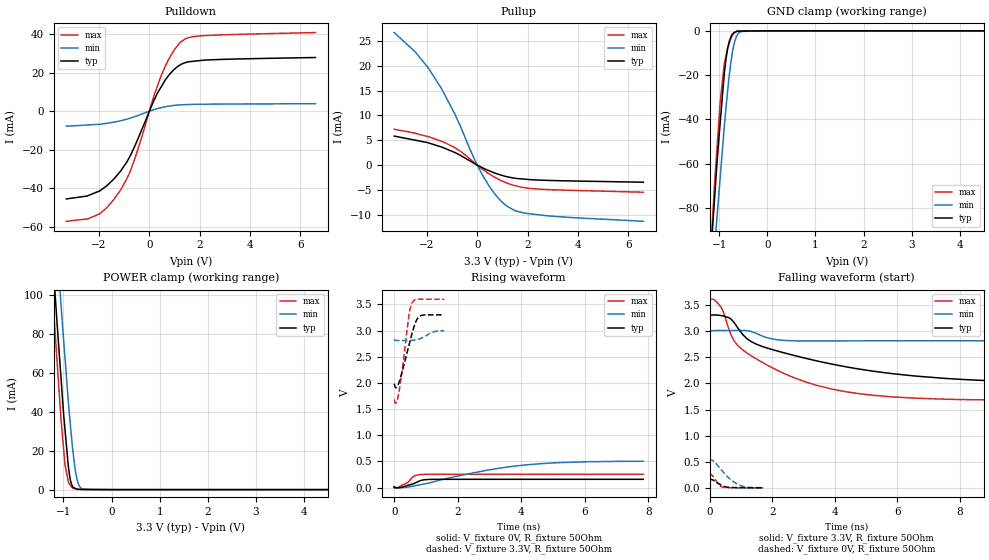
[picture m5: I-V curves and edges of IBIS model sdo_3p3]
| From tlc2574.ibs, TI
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|   sdo_3p3 Model
[Model]   sdo_3p3
Model_type   3-state
Polarity   Non-Inverting
Vmeas = 1.65
Vref = 1.65
Cref = 2pF
Rref = 50
|   typ   min   max
C_comp   1.252e-12   1.247e-12   1.334e-12
[Voltage Range]   3.3   3   3.6
|Ambient Temperature   25   85   -40
|Junction Temperature
[Temperature Range]   27   125   -40
[Pullup Reference]   3.3   3   3.6
[Pulldown Reference]   0   0   0
[Power Clamp Reference]   3.3   3   3.6
[GND Clamp Reference]   0   0   0
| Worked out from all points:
|   slope of the pulldown table from 0 to 0.495 V, typ, clamps not added: 37.5 ohm
|   slope of the pullup table from 0 to 0.495 V, typ, clamps not added: 415 ohm
|   GND clamp passes 1 mA (typ) near -0.70 V on its own axis
|   POWER clamp passes 1 mA (typ) near -0.79 V on its own axis
|   falling waveform, V_fixture 3.3V, R_fixture 50Ohm: 20-80 % time 4.08ns typ, 538ps min, 2.41ns max; typ from 3.3 V to 1.99 V
|   rising waveform, V_fixture 0V, R_fixture 50Ohm: 20-80 % time 423ps typ, 2.51ns min, 324ps max; typ from 0 V to 0.157 V
|   rising waveform, V_fixture 3.3V, R_fixture 50Ohm: 20-80 % time 342ps typ, 337ps min, 239ps max; typ from 1.98 V to 3.3 V
|   falling waveform, V_fixture 0V, R_fixture 50Ohm: 20-80 % time 268ps typ, 508ps min, 172ps max; typ from 0.157 V to 0.001 V
[Pulldown]
|   Voltage   I(typ)   I(min)   I(max)
-3.3V     -45.52mA   -7.788mA   -57.14mA
-2.444V   -43.84mA   -7.138mA   -55.88mA
-1.969V   -41.36mA   -6.778mA   -53.25mA
-1.134V   -30.95mA   -4.947mA   -40.69mA
-734.4mV  -22.56mA   -3.482mA   -30.43mA
174.9mV   5.391mA    753.1uA    7.611mA
478.8mV   12.83mA    1.859mA    18.69mA
810mV     19.22mA    2.712mA    27.92mA
1.246V    24.24mA    3.317mA    35.95mA
1.454V    25.32mA    3.414mA    37.77mA
2.167V    26.5mA     3.633mA    39.22mA
6.6V      27.87mA    3.884mA    40.82mA
[GND Clamp]
|   Voltage   I(typ)   I(min)   I(max)
-3.3V     -922.7mA   -873.5mA   -986.9mA
-1.211V   -112mA     -132.8mA   -110.7mA
-1.102V   -76.91mA   -99.77mA   -70.34mA
-1.056V   -62.3mA    -86.52mA   -55.75mA
-982.8mV  -42.01mA   -66.74mA   -32.51mA
-896.4mV  -19.48mA   -43.41mA   -14.99mA
-861.3mV  -12.87mA   -35.02mA   -11.28mA
-756mV    -2.692mA   -13.81mA   -3.279mA
-648mV    -381.4uA   -2.804mA   -327uA
-552mV    -127.7uA   -329.8uA   -62.08uA
-285mV    -65.55uA   -302.6nA   -104.3nA
6.6V      0A         0A         0A
[Pullup]
|   Voltage   I(typ)   I(min)   I(max)
-3.3V     5.835mA    26.67mA    7.196mA
-2.46V    5.002mA    22.76mA    6.382mA
-1.932V   4.453mA    19.45mA    5.697mA
-1.419V   3.64mA     15.36mA    4.786mA
-897mV    2.549mA    10.32mA    3.531mA
-159mV    451.6uA    1.703mA    671.7uA
228mV     -593.2uA   -2.193mA   -897.2uA
690mV     -1.592mA   -5.779mA   -2.433mA
1.155V    -2.313mA   -8.194mA   -3.58mA
1.86V     -2.826mA   -9.646mA   -4.543mA
2.781V    -3.081mA   -10.21mA   -4.93mA
6.6V      -3.456mA   -11.32mA   -5.468mA
[POWER Clamp]
|   Voltage   I(typ)   I(min)   I(max)
-3.3V     968.7mA    980.7mA    975.5mA
-1.356V   169.5mA    206.7mA    152.6mA
-1.195V   108.6mA    146.8mA    88.93mA
-1.185V   104.8mA    143.1mA    85.09mA
-1.139V   87.74mA    126.6mA    68.23mA
-1.051V   57.71mA    95.77mA    36.57mA
-968.4mV  31.07mA    68.06mA    12.9mA
-897.6mV  11.81mA    45.18mA    3.912mA
-806.4mV  1.497mA    20.64mA    866.2uA
-714mV    214.9uA    4.938mA    373.3uA
-591mV    104.7uA    223.6uA    35.79uA
6.6V      0A         0A         0A
[Ramp]
R_load = 50
|   typ   min   max
dV/dt_r   0.0940914/4.23437e-10   0.302009/2.5121e-09   0.151352/3.22964e-10
dV/dt_f   0.79027/4.15044e-09   0.111339/5.273e-10   1.15667/2.40425e-09
[Falling Waveform]
V_fixture = 3.3V
V_fixture_min = 3V
V_fixture_max = 3.6V
R_fixture = 50Ohm
|   Time   V(typ)   V(min)   V(max)
0s        3.3V       3V         3.6V
145ps     3.309V     3.011V     3.601V
365ps     3.299V     3.012V     3.458V
755ps     3.183V     3.013V     2.844V
1.055ns   2.937V     3.013V     2.64V
1.725ns   2.697V     2.896V     2.388V
2.735ns   2.529V     2.814V     2.1V
3.95ns    2.363V     2.813V     1.886V
8.03ns    2.077V     2.814V     1.691V
14.85ns   1.991V     2.814V     1.673V
[Rising Waveform]
V_fixture = 0V
V_fixture_min = 0V
V_fixture_max = 0V
R_fixture = 50Ohm
|   Time   V(typ)   V(min)   V(max)
0s        1.558nV    3.443nV    1.357nV
5ps       17.43mV    6.245mV    16.31mV
105ps     -6.062mV   -4.033mV   -2.137mV
410ps     37.81mV    6.946mV    89.24mV
630ps     77.34mV    30.53mV    217.5mV
895ps     142.5mV    60.85mV    250.1mV
2.795ns   156.8mV    316.3mV    252.2mV
4.115ns   156.8mV    430.2mV    252.2mV
5.285ns   156.8mV    477.8mV    252.2mV
7.845ns   156.8mV    502.3mV    252.2mV
[Rising Waveform]
V_fixture = 3.3V
V_fixture_min = 3V
V_fixture_max = 3.6V
R_fixture = 50Ohm
|   Time   V(typ)   V(min)   V(max)
0s        1.983V     2.814V     1.672V
65ps      1.909V     2.81V      1.621V
145ps     1.997V     2.809V     1.808V
265ps     2.249V     2.81V      2.309V
470ps     2.73V      2.811V     3.311V
560ps     2.939V     2.813V     3.523V
700ps     3.193V     2.824V     3.595V
835ps     3.283V     2.848V     3.601V
1.23ns    3.3V       2.973V     3.599V
1.575ns   3.3V       2.998V     3.599V
[Falling Waveform]
V_fixture = 0V
V_fixture_min = 0V
V_fixture_max = 0V
R_fixture = 50Ohm
|   Time   V(typ)   V(min)   V(max)
0s        156.8mV    503.3mV    252.3mV
50ps      160.6mV    530.1mV    255.3mV
120ps     145.7mV    514mV      214.9mV
270ps     88.57mV    418.8mV    75.05mV
400ps     43.33mV    325.7mV    18.79mV
545ps     14.99mV    230.5mV    6.913mV
680ps     7.406mV    155.7mV    3.521mV
965ps     4.201mV    50.33mV    1.11mV
1.225ns   2.023mV    11.73mV    757.3uV
1.715ns   712.6uV    3.15mV     658.5uV
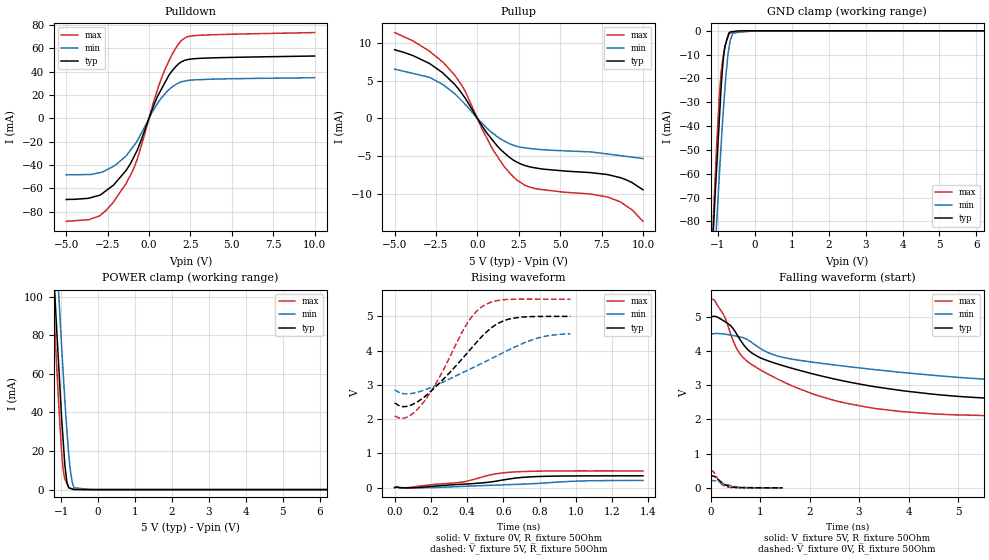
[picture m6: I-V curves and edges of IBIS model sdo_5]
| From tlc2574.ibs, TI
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|   sdo_5 Model
[Model]   sdo_5
Model_type   3-state
Polarity   Non-Inverting
Vmeas = 2.5
Vref = 2.5
Cref = 2pF
Rref = 50
|   typ   min   max
C_comp   1.148e-12   1.143e-12   1.168e-12
[Voltage Range]   5   4.5   5.5
|Ambient Temperature   25   85   -40
|Junction Temperature
[Temperature Range]   27   125   -40
[Pullup Reference]   5   4.5   5.5
[Pulldown Reference]   0   0   0
[Power Clamp Reference]   5   4.5   5.5
[GND Clamp Reference]   0   0   0
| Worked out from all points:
|   slope of the pulldown table from 0 to 0.75 V, typ, clamps not added: 30 ohm
|   slope of the pullup table from 0 to 0.75 V, typ, clamps not added: 310 ohm
|   GND clamp passes 1 mA (typ) near -0.71 V on its own axis
|   POWER clamp passes 1 mA (typ) near -0.79 V on its own axis
|   falling waveform, V_fixture 5V, R_fixture 50Ohm: 20-80 % time 2.73ns typ, 4.54ns min, 1.69ns max; typ from 5 V to 2.46 V
|   rising waveform, V_fixture 0V, R_fixture 50Ohm: 20-80 % time 377ps typ, 510ps min, 316ps max; typ from 0 V to 0.343 V
|   rising waveform, V_fixture 5V, R_fixture 50Ohm: 20-80 % time 264ps typ, 382ps min, 207ps max; typ from 2.47 V to 5 V
|   falling waveform, V_fixture 0V, R_fixture 50Ohm: 20-80 % time 191ps typ, 287ps min, 139ps max; typ from 0.343 V to 0.001 V
[Pulldown]
|   Voltage   I(typ)   I(min)   I(max)
-5V       -69.66mA   -48.54mA   -88.35mA
-3.003V   -66.1mA    -46.69mA   -83.83mA
-2.195V   -57.87mA   -41.53mA   -72.72mA
-1.375V   -44.56mA   -32.17mA   -55.81mA
-715mV    -27.54mA   -19.58mA   -35.25mA
265mV     10.34mA    6.907mA    13.49mA
803mV     26.37mA    18.32mA    36.21mA
1.364V    39.98mA    26.42mA    53.98mA
1.942V    48.18mA    31.14mA    66.42mA
2.376V    50.4mA     32.4mA     70.04mA
3.08V     51.33mA    33.06mA    71.13mA
10V       53.31mA    34.74mA    73.42mA
[GND Clamp]
|   Voltage   I(typ)   I(min)   I(max)
-5V       -1.627A    -1.531A    -1.73A
-1.14V    -88.66mA   -111.8mA   -84.28mA
-1.117V   -81.22mA   -104.6mA   -75.56mA
-1.034V   -56.96mA   -80.53mA   -47.72mA
-968mV    -38.71mA   -62.07mA   -28.66mA
-913mV    -23.51mA   -47.68mA   -17.43mA
-815mV    -6.769mA   -25.03mA   -7.262mA
-729mV    -2.245mA   -9.95mA    -2.514mA
-670mV    -468.2uA   -4.148mA   -872.3uA
-598.5mV  -325.9uA   -1mA       -779.2uA
-202.5mV  -337.9nA   -29.38nA   -263.6uA
10V       0A         0A         0A
[Pullup]
|   Voltage   I(typ)   I(min)   I(max)
-5V       9.102mA    6.533mA    11.38mA
-2.95V    7.343mA    5.483mA    8.994mA
-1.375V   4.523mA    3.296mA    5.76mA
-715mV    2.626mA    1.839mA    3.512mA
319mV     -1.106mA   -711.2uA   -1.546mA
968mV     -3.011mA   -2.011mA   -4.248mA
1.672V    -4.64mA    -3.037mA   -6.521mA
2.376V    -5.766mA   -3.687mA   -8.128mA
3.58V     -6.573mA   -4.065mA   -9.327mA
7.865V    -7.425mA   -4.702mA   -10.39mA
9.35V     -8.501mA   -5.119mA   -12.11mA
10V       -9.44mA    -5.301mA   -13.61mA
[POWER Clamp]
|   Voltage   I(typ)   I(min)   I(max)
-5V       1.705A     1.696A     1.733A
-1.238V   126mA      162.7mA    107.8mA
-1.14V    89.14mA    127.5mA    70.38mA
-1.056V   60.15mA    97.46mA    40.1mA
-951.5mV  26.67mA    62.23mA    11.16mA
-900mV    12.63mA    45.92mA    5.471mA
-850mV    4.374mA    31.94mA    3.345mA
-792mV    972.7uA    17.37mA    879.2uA
-702mV    307.7uA    3.842mA    412.6uA
-643.5mV  78.45uA    931.9uA    109.3uA
-202.5mV  109.5nA    0A         34.4uA
10V       0A         0A         0A
[Ramp]
R_load = 50
|   typ   min   max
dV/dt_r   0.205709/3.76426e-10   0.125317/5.10432e-10   0.291529/3.15827e-10
dV/dt_f   1.51819/2.71166e-09   0.988687/4.56515e-09   2.04804/1.68788e-09
[Falling Waveform]
V_fixture = 5V
V_fixture_min = 4.5V
V_fixture_max = 5.5V
R_fixture = 50Ohm
|   Time   V(typ)   V(min)   V(max)
0s        5V         4.5V       5.5V
270ps     4.877V     4.499V     5.042V
400ps     4.747V     4.467V     4.524V
590ps     4.345V     4.413V     3.928V
850ps     3.927V     4.231V     3.587V
1.42ns    3.591V     3.829V     3.134V
2.17ns    3.294V     3.653V     2.696V
3.26ns    2.971V     3.465V     2.336V
6.89ns    2.536V     3.063V     2.091V
14.31ns   2.463V     2.857V     2.085V
[Rising Waveform]
V_fixture = 0V
V_fixture_min = 0V
V_fixture_max = 0V
R_fixture = 50Ohm
|   Time   V(typ)   V(min)   V(max)
0s        2.028nV    2.53nV     1.859nV
10ps      16.33mV    19.16mV    13.35mV
70ps      -8.228mV   -5.873mV   -2.035mV
200ps     32.59mV    -1.428mV   83.22mV
370ps     96.91mV    32.87mV    159.5mV
540ps     171.3mV    68.56mV    383.9mV
660ps     273.2mV    90.97mV    456.3mV
790ps     322.6mV    121.9mV    479.5mV
1.02ns    341mV      191.5mV    487.2mV
1.37ns    343.1mV    208.4mV    486.4mV
[Rising Waveform]
V_fixture = 5V
V_fixture_min = 4.5V
V_fixture_max = 5.5V
R_fixture = 50Ohm
|   Time   V(typ)   V(min)   V(max)
0s        2.47V      2.852V     2.087V
70ps      2.376V     2.737V     2.06V
150ps     2.592V     2.823V     2.431V
240ps     3.014V     3.016V     3.154V
400ps     3.927V     3.42V      4.792V
490ps     4.458V     3.652V     5.31V
560ps     4.762V     3.837V     5.456V
640ps     4.931V     4.047V     5.498V
800ps     4.997V     4.382V     5.502V
970ps     5V         4.491V     5.5V
[Falling Waveform]
V_fixture = 0V
V_fixture_min = 0V
V_fixture_max = 0V
R_fixture = 50Ohm
|   Time   V(typ)   V(min)   V(max)
0s        342.8mV    208.9mV    485.9mV
50ps      347.4mV    213.8mV    484.6mV
100ps     313.3mV    204mV      371.5mV
150ps     252.5mV    185mV      240.3mV
200ps     188mV      161.3mV    142.8mV
260ps     121.2mV    130.4mV    69.59mV
330ps     65.66mV    96.49mV    27.75mV
440ps     23.76mV    53.36mV    9.726mV
630ps     7.823mV    15.97mV    2.905mV
1.46ns    1.071mV    1.811mV    1.124mV
